VERSION 5.7 ;
  NOWIREEXTENSIONATPIN ON ;
  DIVIDERCHAR "/" ;
  BUSBITCHARS "[]" ;
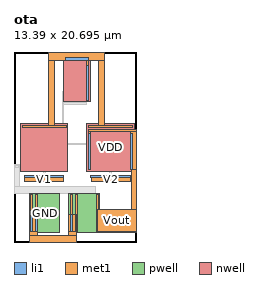
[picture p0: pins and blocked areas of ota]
MACRO ota
  CLASS BLOCK ;
  FOREIGN ota ;
  ORIGIN -0.485 -0.215 ;
  SIZE 13.390 BY 20.695 ;
  PIN V1
    ANTENNAGATEAREA 16.000000 ;
    PORT
      LAYER li1 ;
        RECT 1.635 7.245 5.915 7.475 ;
      LAYER met1 ;
        RECT 1.635 7.225 5.915 7.495 ;
        RECT 1.645 6.825 5.885 7.225 ;
    END
  END V1
  PIN V2
    ANTENNAGATEAREA 16.000000 ;
    PORT
      LAYER li1 ;
        RECT 8.860 7.245 13.140 7.475 ;
      LAYER met1 ;
        RECT 8.860 7.225 13.140 7.495 ;
        RECT 8.880 6.825 13.120 7.225 ;
    END
  END V2
  PIN GND
    ANTENNADIFFAREA 4.440000 ;
    PORT
      LAYER pwell ;
        RECT 2.135 1.215 5.485 5.475 ;
        RECT 6.445 1.215 9.795 5.475 ;
      LAYER li1 ;
        RECT 2.275 1.345 2.545 5.345 ;
        RECT 2.865 1.345 3.035 5.345 ;
        RECT 6.585 1.345 6.855 5.345 ;
        RECT 7.175 1.345 7.345 5.345 ;
      LAYER met1 ;
        RECT 2.275 3.080 2.545 5.345 ;
        RECT 2.835 3.080 3.065 5.345 ;
        RECT 6.585 3.220 6.855 5.345 ;
        RECT 7.145 3.220 7.375 5.345 ;
        RECT 2.120 1.345 3.065 3.080 ;
        RECT 6.455 1.345 7.375 3.220 ;
        RECT 2.120 0.945 3.020 1.345 ;
        RECT 6.455 0.945 7.320 1.345 ;
        RECT 2.120 0.215 7.320 0.945 ;
    END
  END GND
  PIN Vout
    ANTENNADIFFAREA 3.180000 ;
    PORT
      LAYER li1 ;
        RECT 8.635 8.085 8.805 12.085 ;
        RECT 13.195 8.085 13.365 12.085 ;
        RECT 9.455 1.345 9.625 5.345 ;
      LAYER met1 ;
        RECT 8.605 12.435 13.395 12.485 ;
        RECT 8.605 12.255 13.875 12.435 ;
        RECT 8.605 8.085 8.835 12.255 ;
        RECT 13.165 8.085 13.875 12.255 ;
        RECT 9.425 3.730 9.655 5.345 ;
        RECT 13.300 3.730 13.875 8.085 ;
        RECT 9.425 1.345 13.875 3.730 ;
        RECT 9.495 1.215 13.875 1.345 ;
    END
  END Vout
  PIN VDD
    ANTENNADIFFAREA 4.583500 ;
    PORT
      LAYER nwell ;
        RECT 5.915 15.465 8.805 20.455 ;
        RECT 1.190 7.905 6.360 13.135 ;
        RECT 8.415 7.905 13.585 13.135 ;
      LAYER li1 ;
        RECT 6.105 19.995 8.615 20.265 ;
        RECT 8.415 15.645 8.585 19.645 ;
        RECT 1.380 12.675 6.170 12.945 ;
        RECT 8.605 12.675 13.395 12.945 ;
      LAYER met1 ;
        RECT 4.245 19.995 10.335 20.910 ;
        RECT 4.245 12.945 4.910 19.995 ;
        RECT 8.375 19.415 8.650 19.995 ;
        RECT 8.385 15.645 8.615 19.415 ;
        RECT 9.645 12.945 10.310 19.995 ;
        RECT 1.380 12.675 6.170 12.945 ;
        RECT 8.605 12.675 13.395 12.945 ;
    END
  END VDD
  OBS
      LAYER li1 ;
        RECT 6.135 15.645 6.305 19.645 ;
        RECT 6.360 15.205 8.360 15.435 ;
        RECT 1.410 8.085 1.580 12.085 ;
        RECT 3.690 8.085 3.860 12.085 ;
        RECT 5.970 8.085 6.140 12.085 ;
        RECT 10.915 8.085 11.085 12.085 ;
        RECT 3.090 5.555 5.090 5.785 ;
        RECT 7.400 5.555 9.400 5.785 ;
        RECT 5.145 1.345 5.315 5.345 ;
      LAYER met1 ;
        RECT 6.105 16.565 6.335 19.645 ;
        RECT 5.760 15.645 6.335 16.565 ;
        RECT 5.760 15.475 6.305 15.645 ;
        RECT 5.760 15.455 6.605 15.475 ;
        RECT 5.760 15.185 8.360 15.455 ;
        RECT 5.760 15.140 6.605 15.185 ;
        RECT 1.380 12.255 6.170 12.485 ;
        RECT 0.485 6.210 1.130 8.645 ;
        RECT 1.380 8.085 1.610 12.255 ;
        RECT 3.660 8.855 3.890 12.085 ;
        RECT 5.940 11.110 6.170 12.255 ;
        RECT 10.885 11.110 11.115 12.085 ;
        RECT 5.755 10.750 6.330 11.110 ;
        RECT 10.720 10.750 11.295 11.110 ;
        RECT 3.500 8.260 4.075 8.855 ;
        RECT 3.660 7.685 3.890 8.260 ;
        RECT 5.940 8.085 6.170 10.750 ;
        RECT 10.885 7.685 11.115 10.750 ;
        RECT 0.485 5.540 9.410 6.210 ;
        RECT 3.090 5.535 5.360 5.540 ;
        RECT 7.400 5.535 9.400 5.540 ;
        RECT 5.075 3.525 5.360 5.535 ;
        RECT 5.115 1.345 5.345 3.525 ;
      LAYER met2 ;
        RECT 5.760 16.235 5.915 16.565 ;
        RECT 5.760 15.915 6.090 16.235 ;
        RECT 5.760 11.090 5.915 15.915 ;
        RECT 5.760 10.975 6.080 11.090 ;
        RECT 10.830 10.975 11.090 11.070 ;
        RECT 5.760 10.830 11.150 10.975 ;
        RECT 5.760 10.770 6.080 10.830 ;
        RECT 5.760 10.765 5.915 10.770 ;
        RECT 10.830 10.750 11.090 10.830 ;
        RECT 3.705 8.640 3.965 8.755 ;
        RECT 0.485 8.495 4.075 8.640 ;
        RECT 0.665 8.280 0.925 8.495 ;
        RECT 3.705 8.435 3.965 8.495 ;
  END
END ota
END LIBRARY

